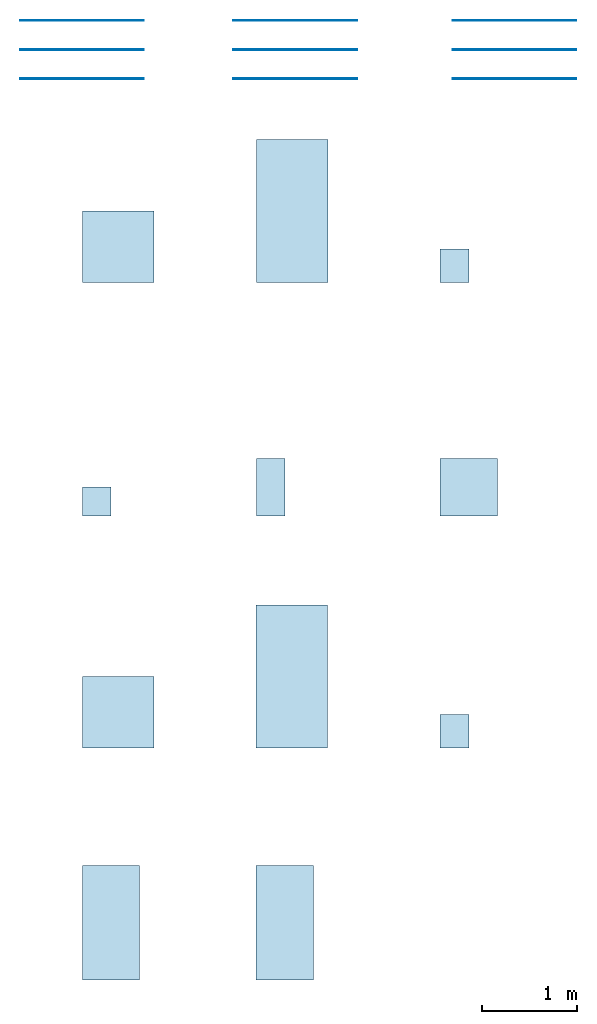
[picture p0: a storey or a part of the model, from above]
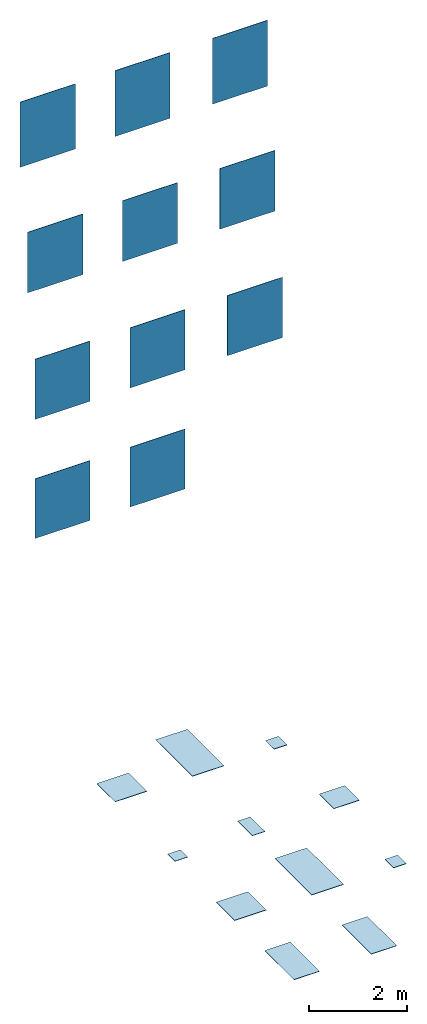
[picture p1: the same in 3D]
Properties of the parts of a building model (IFC2X3)

# File
Description: ViewDefinition [CoordinationView_V2.0], RevitIdentifiers [VersionGUID: 1a7853d5-8258-4d92-be9f-6eaaf23e1352, NumberOfSaves: 259], CoordinateReference [CoordinateBase: Shared Coordinates, ProjectSite: Internal]
File name: Project Number
Time: 2025-02-25T10:54:23+01:00
Written by: ODA SDAI 24.3
Made in: Autodesk Revit 24.1.11.26 (ENU) - IFC 24.1.11.26

# IfcProject, Project Number
LongName: Refin-Blended; Phase: Project Status

# IfcSite, Default
RefLatitude: 51, 30, 0, 549316; RefLongitude: 0, -7, -34, -450321; RefElevation: 0 mm

# IfcBuilding
Pset_BuildingCommon - NumberOfStoreys: 1

# IfcBuildingStorey: Level:Circle Head - Project Datum (2)
Pset_AirSideSystemInformation - sets with these values: 2
Name | LongName = Name | Elevation (mm)
Level 0 | Level 0 | 0
Level 1 | Level 1 | 4000

# IfcSlab: Floor:Floor_Tiles_Refin-Prestigio_Travertino-Beige-Lucido-75x150 OM86, Floor:Floor_Tiles_Refin-Prestigio_Travertino-Beige-Lucido-75x150 OM86:324498
In: Level 0
Type - PredefinedType: FLOOR; Material: Prestigio Travertino-Beige-Lucido-75x150 OM86 9 mm, <Unnamed> 1 mm
Type - Pset_ConcreteElementGeneral - FireRating: INERT
Type - Pset_ElementShading - Color: IVORY-BEIGE
Type - Pset_FireRatingProperties - SurfaceSpreadOfFlame: INERT
Type - Pset_ManufacturerOccurrence - BarCode: N/A; SerialNumber: N/A
Type - Pset_ManufacturerTypeInformation - ArticleNumber: OM86; ModelReference: OM86; ModelLabel: BEIGE LUCIDO 75X150; Manufacturer: info@refin.it; ProductionYear: N/A
Type - Pset_PrecastConcreteElementGeneral - SerialNumber: N/A
Type - Pset_ProductRequirements - Name: Prestigio_Travertino_Beige_Lucido_75X150; Category: Pr_35_93_96_19:Ceramic tiles
Type - Pset_QuantityTakeOff - Reference: N/A
Type - Pset_ReinforcementBarPitchOfSlab - Description: PORCELAIN STONEWARE TILE; Reference: N/A
Type - Pset_SlabCommon - Reference: N/A; IsExternal: no; AcousticRating: N/A; FireRating: INERT; SurfaceSpreadOfFlame: INERT
Type - Pset_Warranty - WarrantyContent: N/A; Exclusions: N/A
Pset_QuantityTakeOff - sets with these values: 2
Pset_SlabCommon - LoadBearing: no; PitchAngle: 0 deg

# IfcSlab: Floor:Floor_Tiles_Refin-Prestigio_Travertino-Beige-Lucido-75x75 OO01, Floor:Floor_Tiles_Refin-Prestigio_Travertino-Beige-Lucido-75x75 OO01:304668
In: Level 0
Type - PredefinedType: FLOOR; Material: Prestigio Travertino-Beige-Lucido-75x75 OO01 9 mm, <Unnamed> 1 mm
Type - Pset_ConcreteElementGeneral - FireRating: INERT
Type - Pset_ElementShading - Color: IVORY-BEIGE
Type - Pset_FireRatingProperties - SurfaceSpreadOfFlame: INERT
Type - Pset_ManufacturerOccurrence - BarCode: N/A; SerialNumber: N/A
Type - Pset_ManufacturerTypeInformation - ArticleNumber: OO01; ModelReference: OO01; ModelLabel: BEIGE LUCIDO 75X75; Manufacturer: info@refin.it; ProductionYear: N/A
Type - Pset_PrecastConcreteElementGeneral - SerialNumber: N/A
Type - Pset_ProductRequirements - Name: Prestigio_Travertino_Beige_Lucido_75X75; Category: Pr_35_93_96_19:Ceramic tiles
Type - Pset_QuantityTakeOff - Reference: N/A
Type - Pset_ReinforcementBarPitchOfSlab - Description: PORCELAIN STONEWARE TILE; Reference: N/A
Type - Pset_SlabCommon - Reference: N/A; IsExternal: no; AcousticRating: N/A; FireRating: INERT; SurfaceSpreadOfFlame: INERT
Type - Pset_Warranty - WarrantyContent: N/A; Exclusions: N/A
Pset_QuantityTakeOff - sets with these values: 2
Pset_SlabCommon - LoadBearing: no; PitchAngle: 0 deg

# IfcSlab: Floor:Floor_Tiles_Refin-Prestigio_Travertino-Beige-Lucido-Mosaico-Cube 30.4x35.2 OO30, Floor:Floor_Tiles_Refin-Prestigio_Travertino-Beige-Lucido-Mosaico-Cube 30.4x35.2 OO30:285295
In: Level 0
Type - PredefinedType: FLOOR; Material: Prestigio Travertino-Beige-Lucido-Mosaico-Cube 30.4x35.2 OO30 9 mm, <Unnamed> 1 mm
Type - Pset_ConcreteElementGeneral - FireRating: INERT
Type - Pset_ElementShading - Color: IVORY-BEIGE
Type - Pset_FireRatingProperties - SurfaceSpreadOfFlame: INERT
Type - Pset_ManufacturerOccurrence - BarCode: N/A; SerialNumber: N/A
Type - Pset_ManufacturerTypeInformation - ArticleNumber: OO30; ModelReference: OO30; ModelLabel: BEIGE LUCIDO MOSAICO CUBE 30.4X35.2; Manufacturer: info@refin.it; ProductionYear: N/A
Type - Pset_PrecastConcreteElementGeneral - SerialNumber: N/A
Type - Pset_ProductRequirements - Name: Prestigio_Travertino_Beige_Lucido_Mosaico_Cube_30.4X35.2; Category: Pr_35_93_96_19:Ceramic tiles
Type - Pset_QuantityTakeOff - Reference: N/A
Type - Pset_ReinforcementBarPitchOfSlab - Description: PORCELAIN STONEWARE TILE; Reference: N/A
Type - Pset_SlabCommon - Reference: N/A; IsExternal: no; AcousticRating: N/A; FireRating: INERT; SurfaceSpreadOfFlame: INERT
Type - Pset_Warranty - WarrantyContent: N/A; Exclusions: N/A
Pset_QuantityTakeOff - sets with these values: 2
Pset_SlabCommon - LoadBearing: no; PitchAngle: 0 deg

# IfcSlab: Floor:Floor_Tiles_Refin-Prestigio_Travertino-Beige-Lucido-Mosaico-T 30x30 OO36, Floor:Floor_Tiles_Refin-Prestigio_Travertino-Beige-Lucido-Mosaico-T 30x30 OO36:304956
In: Level 0
Type - PredefinedType: FLOOR; Material: Prestigio Travertino-Beige-Mix-Mosaico-T 30x30 OO36 9 mm, <Unnamed> 1 mm
Type - Pset_ConcreteElementGeneral - FireRating: INERT
Type - Pset_ElementShading - Color: IVORY-BEIGE
Type - Pset_FireRatingProperties - SurfaceSpreadOfFlame: INERT
Type - Pset_ManufacturerOccurrence - BarCode: N/A; SerialNumber: N/A
Type - Pset_ManufacturerTypeInformation - ArticleNumber: OO36; ModelReference: OO36; ModelLabel: BEIGE MIX MOSAICO T 3X30; Manufacturer: info@refin.it; ProductionYear: N/A
Type - Pset_PrecastConcreteElementGeneral - SerialNumber: N/A
Type - Pset_ProductRequirements - Name: Prestigio_Travertino_Beige_Mix_Mosaico_T_3X30; Category: Pr_35_93_96_19:Ceramic tiles
Type - Pset_QuantityTakeOff - Reference: N/A
Type - Pset_ReinforcementBarPitchOfSlab - Description: PORCELAIN STONEWARE TILE; Reference: N/A
Type - Pset_SlabCommon - Reference: N/A; IsExternal: no; AcousticRating: N/A; FireRating: INERT; SurfaceSpreadOfFlame: INERT
Type - Pset_Warranty - WarrantyContent: N/A; Exclusions: N/A
Pset_QuantityTakeOff - sets with these values: 2
Pset_SlabCommon - LoadBearing: no; PitchAngle: 0 deg

# IfcSlab: Floor:Floor_Tiles_Refin-Prestigio_Travertino-Beige-Soft-30x60 OO07, Floor:Floor_Tiles_Refin-Prestigio_Travertino-Beige-Soft-30x60 OO07:304948
In: Level 0
Type - PredefinedType: FLOOR; Material: Prestigio Travertino-Beige-Soft-30x60 OO07 9 mm, <Unnamed> 1 mm
Type - Pset_ConcreteElementGeneral - FireRating: INERT
Type - Pset_ElementShading - Color: IVORY-BEIGE
Type - Pset_FireRatingProperties - SurfaceSpreadOfFlame: INERT
Type - Pset_ManufacturerOccurrence - BarCode: N/A; SerialNumber: N/A
Type - Pset_ManufacturerTypeInformation - ArticleNumber: OO07; ModelReference: OO07; ModelLabel: BEIGE SOFT 30X60; Manufacturer: info@refin.it; ProductionYear: N/A
Type - Pset_PrecastConcreteElementGeneral - SerialNumber: N/A
Type - Pset_ProductRequirements - Name: Prestigio_Travertino_Beige_Soft_30X60; Category: Pr_35_93_96_19:Ceramic tiles
Type - Pset_QuantityTakeOff - Reference: N/A
Type - Pset_ReinforcementBarPitchOfSlab - Description: PORCELAIN STONEWARE TILE; Reference: N/A
Type - Pset_SlabCommon - Reference: N/A; IsExternal: no; AcousticRating: N/A; FireRating: INERT; SurfaceSpreadOfFlame: INERT
Type - Pset_Warranty - WarrantyContent: N/A; Exclusions: N/A
Pset_QuantityTakeOff - sets with these values: 2
Pset_SlabCommon - LoadBearing: no; PitchAngle: 0 deg

# IfcSlab: Floor:Floor_Tiles_Refin-Prestigio_Travertino-Beige-Soft-60x120 OZ35, Floor:Floor_Tiles_Refin-Prestigio_Travertino-Beige-Soft-60x120 OZ35:348506
In: Level 0
Type - PredefinedType: FLOOR; Material: Prestigio Travertino-Beige-Soft-60x120 OZ35 9 mm, <Unnamed> 1 mm
Type - Pset_ConcreteElementGeneral - FireRating: INERT
Type - Pset_ElementShading - Color: BEIGE
Type - Pset_FireRatingProperties - SurfaceSpreadOfFlame: INERT
Type - Pset_ManufacturerOccurrence - BarCode: N/A; SerialNumber: N/A
Type - Pset_ManufacturerTypeInformation - ArticleNumber: OZ35; ModelReference: OZ35; ModelLabel: BEIGE SOFT 60X120; Manufacturer: info@refin.it; ProductionYear: N/A
Type - Pset_PrecastConcreteElementGeneral - SerialNumber: N/A
Type - Pset_ProductRequirements - Name: Prestigio_Travertino_Beige_Soft_60X120; Category: Pr_35_93_96_19:Ceramic tiles
Type - Pset_QuantityTakeOff - Reference: N/A
Type - Pset_ReinforcementBarPitchOfSlab - Description: PORCELAIN STONEWARE TILE; Reference: N/A
Type - Pset_SlabCommon - Reference: N/A; IsExternal: no; AcousticRating: N/A; FireRating: INERT; SurfaceSpreadOfFlame: INERT
Type - Pset_Warranty - WarrantyContent: N/A; Exclusions: N/A
Pset_QuantityTakeOff - sets with these values: 2
Pset_SlabCommon - LoadBearing: no; PitchAngle: 0 deg

# IfcSlab: Floor:Floor_Tiles_Refin-Prestigio_Travertino-Beige-Soft-60x60 OO04, Floor:Floor_Tiles_Refin-Prestigio_Travertino-Beige-Soft-60x60 OO04:304932
In: Level 0
Type - PredefinedType: FLOOR; Material: Prestigio Travertino-Beige-Soft-60x60 OO04 9 mm, <Unnamed> 1 mm
Type - Pset_ConcreteElementGeneral - FireRating: INERT
Type - Pset_ElementShading - Color: IVORY-BEIGE
Type - Pset_FireRatingProperties - SurfaceSpreadOfFlame: INERT
Type - Pset_ManufacturerOccurrence - BarCode: N/A; SerialNumber: N/A
Type - Pset_ManufacturerTypeInformation - ArticleNumber: OO04; ModelReference: OO04; ModelLabel: BEIGE SOFT 60X60; Manufacturer: info@refin.it; ProductionYear: N/A
Type - Pset_PrecastConcreteElementGeneral - SerialNumber: N/A
Type - Pset_ProductRequirements - Name: Prestigio_Travertino_Beige_Soft_60X60; Category: Pr_35_93_96_19:Ceramic tiles
Type - Pset_QuantityTakeOff - Reference: N/A
Type - Pset_ReinforcementBarPitchOfSlab - Description: PORCELAIN STONEWARE TILE; Reference: N/A
Type - Pset_SlabCommon - Reference: N/A; IsExternal: no; AcousticRating: N/A; FireRating: INERT; SurfaceSpreadOfFlame: INERT
Type - Pset_Warranty - WarrantyContent: N/A; Exclusions: N/A
Pset_QuantityTakeOff - sets with these values: 2
Pset_SlabCommon - LoadBearing: no; PitchAngle: 0 deg

# IfcSlab: Floor:Floor_Tiles_Refin-Prestigio_Travertino-Beige-Soft-75x150 OM83, Floor:Floor_Tiles_Refin-Prestigio_Travertino-Beige-Soft-75x150 OM83:339635
In: Level 0
Type - PredefinedType: FLOOR; Material: Prestigio Travertino-Beige-Soft-75x150 OM83 9 mm, <Unnamed> 1 mm
Type - Pset_ConcreteElementGeneral - FireRating: INERT
Type - Pset_ElementShading - Color: IVORY-BEIGE
Type - Pset_FireRatingProperties - SurfaceSpreadOfFlame: INERT
Type - Pset_ManufacturerOccurrence - BarCode: N/A; SerialNumber: N/A
Type - Pset_ManufacturerTypeInformation - ArticleNumber: OM83; ModelReference: OM83; ModelLabel: BEIGE SOFT 75X150; Manufacturer: info@refin.it; ProductionYear: N/A
Type - Pset_PrecastConcreteElementGeneral - SerialNumber: N/A
Type - Pset_ProductRequirements - Name: Prestigio_Travertino_Beige_Soft_75X150; Category: Pr_35_93_96_19:Ceramic tiles
Type - Pset_QuantityTakeOff - Reference: N/A
Type - Pset_ReinforcementBarPitchOfSlab - Description: PORCELAIN STONEWARE TILE; Reference: N/A
Type - Pset_SlabCommon - Reference: N/A; IsExternal: no; AcousticRating: N/A; FireRating: INERT; SurfaceSpreadOfFlame: INERT
Type - Pset_Warranty - WarrantyContent: N/A; Exclusions: N/A
Pset_QuantityTakeOff - sets with these values: 2
Pset_SlabCommon - LoadBearing: no; PitchAngle: 0 deg

# IfcSlab: Floor:Floor_Tiles_Refin-Prestigio_Travertino-Beige-Soft-75x75 ON98, Floor:Floor_Tiles_Refin-Prestigio_Travertino-Beige-Soft-75x75 ON98:305509
In: Level 0
Type - PredefinedType: FLOOR; Material: Prestigio Travertino-Beige-Soft-75x75 ON98 9 mm, <Unnamed> 1 mm
Type - Pset_ConcreteElementGeneral - FireRating: INERT
Type - Pset_ElementShading - Color: IVORY-BEIGE
Type - Pset_FireRatingProperties - SurfaceSpreadOfFlame: INERT
Type - Pset_ManufacturerOccurrence - BarCode: N/A; SerialNumber: N/A
Type - Pset_ManufacturerTypeInformation - ArticleNumber: ON98; ModelReference: ON98; ModelLabel: BEIGE SOFT 75X75; Manufacturer: info@refin.it; ProductionYear: N/A
Type - Pset_PrecastConcreteElementGeneral - SerialNumber: N/A
Type - Pset_ProductRequirements - Name: Prestigio_Travertino_Beige_Soft_75X75; Category: Pr_35_93_96_19:Ceramic tiles
Type - Pset_QuantityTakeOff - Reference: N/A
Type - Pset_ReinforcementBarPitchOfSlab - Description: PORCELAIN STONEWARE TILE; Reference: N/A
Type - Pset_SlabCommon - Reference: N/A; IsExternal: no; AcousticRating: N/A; FireRating: INERT; SurfaceSpreadOfFlame: INERT
Type - Pset_Warranty - WarrantyContent: N/A; Exclusions: N/A
Pset_QuantityTakeOff - sets with these values: 2
Pset_SlabCommon - LoadBearing: no; PitchAngle: 0 deg

# IfcSlab: Floor:Floor_Tiles_Refin-Prestigio_Travertino-Beige-Soft-Mosaico-Cube 30.4x35.2 OO33, Floor:Floor_Tiles_Refin-Prestigio_Travertino-Beige-Soft-Mosaico-Cube 30.4x35.2 OO33:339650
In: Level 0
Type - PredefinedType: FLOOR; Material: Prestigio Travertino-Beige-Soft-Mosaico-Cube 30.4x35.2 OO33 9 mm, <Unnamed> 1 mm
Type - Pset_ConcreteElementGeneral - FireRating: INERT
Type - Pset_ElementShading - Color: IVORY-BEIGE
Type - Pset_FireRatingProperties - SurfaceSpreadOfFlame: INERT
Type - Pset_ManufacturerOccurrence - BarCode: N/A; SerialNumber: N/A
Type - Pset_ManufacturerTypeInformation - ArticleNumber: OO33; ModelReference: OO33; ModelLabel: BEIGE SOFT MOSAICO CUBE 30.4X35.2; Manufacturer: info@refin.it; ProductionYear: N/A
Type - Pset_PrecastConcreteElementGeneral - SerialNumber: N/A
Type - Pset_ProductRequirements - Name: Prestigio_Travertino_Beige_Soft_Mosaico_Cube_30.4X35.2; Category: Pr_35_93_96_19:Ceramic tiles
Type - Pset_QuantityTakeOff - Reference: N/A
Type - Pset_ReinforcementBarPitchOfSlab - Description: PORCELAIN STONEWARE TILE; Reference: N/A
Type - Pset_SlabCommon - Reference: N/A; IsExternal: no; AcousticRating: N/A; FireRating: INERT; SurfaceSpreadOfFlame: INERT
Type - Pset_Warranty - WarrantyContent: N/A; Exclusions: N/A
Pset_QuantityTakeOff - sets with these values: 2
Pset_SlabCommon - LoadBearing: no; PitchAngle: 0 deg

# IfcSlab: Floor:Floor_Tiles_Refin-Prestigio_Travertino-Dorico-Beige-Soft-60x120 RK78, Floor:Floor_Tiles_Refin-Prestigio_Travertino-Dorico-Beige-Soft-60x120 RK78:349143
In: Level 0
Type - PredefinedType: FLOOR; Material: Prestigio Travertino-Dorico-Beige-Soft-60x120 RK78 9 mm, <Unnamed> 1 mm
Type - Pset_ConcreteElementGeneral - FireRating: INERT
Type - Pset_ElementShading - Color: BEIGE
Type - Pset_FireRatingProperties - SurfaceSpreadOfFlame: INERT
Type - Pset_ManufacturerOccurrence - BarCode: N/A; SerialNumber: N/A
Type - Pset_ManufacturerTypeInformation - ArticleNumber: RK78; ModelReference: RK78; ModelLabel: DORICO BEIGE SOFT 60X120; Manufacturer: info@refin.it; ProductionYear: N/A
Type - Pset_PrecastConcreteElementGeneral - SerialNumber: N/A
Type - Pset_ProductRequirements - Name: Prestigio_Travertino_Dorico_Beige_Soft_60X120; Category: Pr_35_93_96_19:Ceramic tiles
Type - Pset_QuantityTakeOff - Reference: N/A
Type - Pset_ReinforcementBarPitchOfSlab - Description: PORCELAIN STONEWARE TILE; Reference: N/A
Type - Pset_SlabCommon - Reference: N/A; IsExternal: no; AcousticRating: N/A; FireRating: INERT; SurfaceSpreadOfFlame: INERT
Type - Pset_Warranty - WarrantyContent: N/A; Exclusions: N/A
Pset_QuantityTakeOff - sets with these values: 2
Pset_SlabCommon - LoadBearing: no; PitchAngle: 0 deg

# IfcWallStandardCase: Basic Wall:Floor_Tiles_Refin-Prestigio_Travertino-Beige-Lucido-75x150 OM86, Basic Wall:Floor_Tiles_Refin-Prestigio_Travertino-Beige-Lucido-75x150 OM86:333696
In: Level 0
Type - PredefinedType: STANDARD; Material: <Unnamed> 1 mm, Prestigio Travertino-Beige-Lucido-75x150 OM86 9 mm
Type - Pset_ElementShading - Color: IVORY-BEIGE
Type - Pset_FireRatingProperties - SurfaceSpreadOfFlame: INERT
Type - Pset_ManufacturerOccurrence - BarCode: N/A; SerialNumber: N/A
Type - Pset_ManufacturerTypeInformation - ArticleNumber: OM86; ModelReference: OM86; ModelLabel: BEIGE LUCIDO 75X150; Manufacturer: info@refin.it; ProductionYear: N/A
Type - Pset_PrecastConcreteElementGeneral - SerialNumber: N/A
Type - Pset_ProductRequirements - Name: Prestigio Travertino_Beige_Lucido_75X150; Category: Pr_35_93_96_19:Ceramic tiles
Type - Pset_QuantityTakeOff - Reference: N/A
Type - Pset_ReinforcementBarPitchOfWall - Description: PORCELAIN STONEWARE TILE; Reference: N/A
Type - Pset_WallCommon - Reference: N/A; IsExternal: no; AcousticRating: N/A; SurfaceSpreadOfFlame: INERT
Type - Pset_Warranty - WarrantyContent: N/A; Exclusions: N/A
Pset_QuantityTakeOff - sets with these values: 2
Pset_WallCommon - LoadBearing: no; ExtendToStructure: no

# IfcWallStandardCase: Basic Wall:Floor_Tiles_Refin-Prestigio_Travertino-Beige-Lucido-75x75 OO01, Basic Wall:Floor_Tiles_Refin-Prestigio_Travertino-Beige-Lucido-75x75 OO01:334895
In: Level 0
Type - PredefinedType: STANDARD; Material: <Unnamed> 1 mm, Prestigio Travertino-Beige-Lucido-75x75 OO01 9 mm
Type - Pset_ElementShading - Color: IVORY-BEIGE
Type - Pset_FireRatingProperties - SurfaceSpreadOfFlame: INERT
Type - Pset_ManufacturerOccurrence - BarCode: N/A; SerialNumber: N/A
Type - Pset_ManufacturerTypeInformation - ArticleNumber: OO01; ModelReference: OO01; ModelLabel: BEIGE LUCIDO 75X75; Manufacturer: info@refin.it; ProductionYear: N/A
Type - Pset_PrecastConcreteElementGeneral - SerialNumber: N/A
Type - Pset_ProductRequirements - Name: Prestigio Travertino_Beige_Lucido_75X75; Category: Pr_35_93_96_19:Ceramic tiles
Type - Pset_QuantityTakeOff - Reference: N/A
Type - Pset_ReinforcementBarPitchOfWall - Description: PORCELAIN STONEWARE TILE; Reference: N/A
Type - Pset_WallCommon - Reference: N/A; IsExternal: no; AcousticRating: N/A; SurfaceSpreadOfFlame: INERT
Type - Pset_Warranty - WarrantyContent: N/A; Exclusions: N/A
Pset_QuantityTakeOff - sets with these values: 2
Pset_WallCommon - LoadBearing: no; ExtendToStructure: no

# IfcWallStandardCase: Basic Wall:Floor_Tiles_Refin-Prestigio_Travertino-Beige-Lucido-Mosaico-Cube 30.4x35.2 OO30, Basic Wall:Floor_Tiles_Refin-Prestigio_Travertino-Beige-Lucido-Mosaico-Cube 30.4x35.2 OO30:334553
In: Level 0
Type - PredefinedType: STANDARD; Material: <Unnamed> 1 mm, Prestigio Travertino-Beige-Lucido-Mosaico-Cube 30.4x35.2 OO30 9 mm
Type - Pset_ElementShading - Color: IVORY-BEIGE
Type - Pset_FireRatingProperties - SurfaceSpreadOfFlame: INERT
Type - Pset_ManufacturerOccurrence - BarCode: N/A; SerialNumber: N/A
Type - Pset_ManufacturerTypeInformation - ArticleNumber: OO30; ModelReference: OO30; ModelLabel: BEIGE LUCIDO MOSAICO CUBE 30.4X35.2; Manufacturer: info@refin.it; ProductionYear: N/A
Type - Pset_PrecastConcreteElementGeneral - SerialNumber: N/A
Type - Pset_ProductRequirements - Name: Prestigio Travertino_Beige_Lucido_Mosaico_Cube_30.4X35.2; Category: Pr_35_93_96_19:Ceramic tiles
Type - Pset_QuantityTakeOff - Reference: N/A
Type - Pset_ReinforcementBarPitchOfWall - Description: PORCELAIN STONEWARE TILE; Reference: N/A
Type - Pset_WallCommon - Reference: N/A; IsExternal: no; AcousticRating: N/A; SurfaceSpreadOfFlame: INERT
Type - Pset_Warranty - WarrantyContent: N/A; Exclusions: N/A
Pset_QuantityTakeOff - sets with these values: 2
Pset_WallCommon - LoadBearing: no; ExtendToStructure: no

# IfcWallStandardCase: Basic Wall:Floor_Tiles_Refin-Prestigio_Travertino-Beige-Lucido-Mosaico-T 30x30 OO36, Basic Wall:Floor_Tiles_Refin-Prestigio_Travertino-Beige-Lucido-Mosaico-T 30x30 OO36:335038
In: Level 0
Type - PredefinedType: STANDARD; Material: <Unnamed> 1 mm, Prestigio Travertino-Beige-Mix-Mosaico-T 30x30 OO36 9 mm
Type - Pset_ElementShading - Color: IVORY-BEIGE
Type - Pset_FireRatingProperties - SurfaceSpreadOfFlame: INERT
Type - Pset_ManufacturerOccurrence - BarCode: N/A; SerialNumber: N/A
Type - Pset_ManufacturerTypeInformation - ArticleNumber: OO36; ModelReference: OO36; ModelLabel: BEIGE MIX MOSAICO T 30X30; Manufacturer: info@refin.it; ProductionYear: N/A
Type - Pset_PrecastConcreteElementGeneral - SerialNumber: N/A
Type - Pset_ProductRequirements - Name: Prestigio Travertino_BeigeMix_Mosaico_T_30X30; Category: Pr_35_93_96_19:Ceramic tiles
Type - Pset_QuantityTakeOff - Reference: N/A
Type - Pset_ReinforcementBarPitchOfWall - Description: PORCELAIN STONEWARE TILE; Reference: N/A
Type - Pset_WallCommon - Reference: N/A; IsExternal: no; AcousticRating: N/A; SurfaceSpreadOfFlame: INERT
Type - Pset_Warranty - WarrantyContent: N/A; Exclusions: N/A
Pset_QuantityTakeOff - sets with these values: 2
Pset_WallCommon - LoadBearing: no; ExtendToStructure: no

# IfcWallStandardCase: Basic Wall:Floor_Tiles_Refin-Prestigio_Travertino-Beige-Soft-30x60 OO07, Basic Wall:Floor_Tiles_Refin-Prestigio_Travertino-Beige-Soft-30x60 OO07:335490
In: Level 0
Type - PredefinedType: STANDARD; Material: <Unnamed> 1 mm, Prestigio Travertino-Beige-Soft-30x60 OO07 9 mm
Type - Pset_ElementShading - Color: IVORY-BEIGE
Type - Pset_FireRatingProperties - SurfaceSpreadOfFlame: INERT
Type - Pset_ManufacturerOccurrence - BarCode: N/A; SerialNumber: N/A
Type - Pset_ManufacturerTypeInformation - ArticleNumber: OO07; ModelReference: OO07; ModelLabel: BEIGE SOFT 30X60; Manufacturer: info@refin.it; ProductionYear: N/A
Type - Pset_PrecastConcreteElementGeneral - SerialNumber: N/A
Type - Pset_ProductRequirements - Name: Prestigio Travertino_Beige_Soft_30X60; Category: Pr_35_93_96_19:Ceramic tiles
Type - Pset_QuantityTakeOff - Reference: N/A
Type - Pset_ReinforcementBarPitchOfWall - Description: PORCELAIN STONEWARE TILE; Reference: N/A
Type - Pset_WallCommon - Reference: N/A; IsExternal: no; AcousticRating: N/A; SurfaceSpreadOfFlame: INERT
Type - Pset_Warranty - WarrantyContent: N/A; Exclusions: N/A
Pset_QuantityTakeOff - sets with these values: 2
Pset_WallCommon - LoadBearing: no; ExtendToStructure: no

# IfcWallStandardCase: Basic Wall:Floor_Tiles_Refin-Prestigio_Travertino-Beige-Soft-60x120 OZ35, Basic Wall:Floor_Tiles_Refin-Prestigio_Travertino-Beige-Soft-60x120 OZ35:348591
In: Level 0
Type - PredefinedType: STANDARD; Material: <Unnamed> 1 mm, Prestigio Travertino-Beige-Soft-60x120 OZ35 9 mm
Type - Pset_ElementShading - Color: BEIGE
Type - Pset_FireRatingProperties - SurfaceSpreadOfFlame: INERT
Type - Pset_ManufacturerOccurrence - BarCode: N/A; SerialNumber: N/A
Type - Pset_ManufacturerTypeInformation - ArticleNumber: OZ35; ModelReference: OZ35; ModelLabel: BEIGE SOFT 60X120; Manufacturer: info@refin.it; ProductionYear: N/A
Type - Pset_PrecastConcreteElementGeneral - SerialNumber: N/A
Type - Pset_ProductRequirements - Name: Prestigio Travertino_Beige_Soft_60X120; Category: Pr_35_93_96_19:Ceramic tiles
Type - Pset_QuantityTakeOff - Reference: N/A
Type - Pset_ReinforcementBarPitchOfWall - Description: PORCELAIN STONEWARE TILE; Reference: N/A
Type - Pset_WallCommon - Reference: N/A; IsExternal: no; AcousticRating: N/A; SurfaceSpreadOfFlame: INERT
Type - Pset_Warranty - WarrantyContent: N/A; Exclusions: N/A
Pset_QuantityTakeOff - sets with these values: 2
Pset_WallCommon - LoadBearing: no; ExtendToStructure: no

# IfcWallStandardCase: Basic Wall:Floor_Tiles_Refin-Prestigio_Travertino-Beige-Soft-60x60 OO04, Basic Wall:Floor_Tiles_Refin-Prestigio_Travertino-Beige-Soft-60x60 OO04:335882
In: Level 0
Type - PredefinedType: STANDARD; Material: <Unnamed> 1 mm, Prestigio Travertino-Beige-Soft-60x60 OO04 9 mm
Type - Pset_ElementShading - Color: IVORY-BEIGE
Type - Pset_FireRatingProperties - SurfaceSpreadOfFlame: INERT
Type - Pset_ManufacturerOccurrence - BarCode: N/A; SerialNumber: N/A
Type - Pset_ManufacturerTypeInformation - ArticleNumber: OO04; ModelReference: OO04; ModelLabel: BEIGE SOFT 60X60; Manufacturer: info@refin.it; ProductionYear: N/A
Type - Pset_PrecastConcreteElementGeneral - SerialNumber: N/A
Type - Pset_ProductRequirements - Name: Prestigio Travertino_Beige_Soft_60X60; Category: Pr_35_93_96_19:Ceramic tiles
Type - Pset_QuantityTakeOff - Reference: N/A
Type - Pset_ReinforcementBarPitchOfWall - Description: PORCELAIN STONEWARE TILE; Reference: N/A
Type - Pset_WallCommon - Reference: N/A; IsExternal: no; AcousticRating: N/A; SurfaceSpreadOfFlame: INERT
Type - Pset_Warranty - WarrantyContent: N/A; Exclusions: N/A
Pset_QuantityTakeOff - sets with these values: 2
Pset_WallCommon - LoadBearing: no; ExtendToStructure: no

# IfcWallStandardCase: Basic Wall:Floor_Tiles_Refin-Prestigio_Travertino-Beige-Soft-75x150 OM83, Basic Wall:Floor_Tiles_Refin-Prestigio_Travertino-Beige-Soft-75x150 OM83:339715
In: Level 0
Type - PredefinedType: STANDARD; Material: <Unnamed> 1 mm, Prestigio Travertino-Beige-Soft-75x150 OM83 9 mm
Type - Pset_ElementShading - Color: IVORY-BEIGE
Type - Pset_FireRatingProperties - SurfaceSpreadOfFlame: INERT
Type - Pset_ManufacturerOccurrence - BarCode: N/A; SerialNumber: N/A
Type - Pset_ManufacturerTypeInformation - ArticleNumber: OM83; ModelReference: OM83; ModelLabel: BEIGE SOFT 75X150; Manufacturer: info@refin.it; ProductionYear: N/A
Type - Pset_PrecastConcreteElementGeneral - SerialNumber: N/A
Type - Pset_ProductRequirements - Name: Prestigio Travertino_Beige_Soft_75X150; Category: Pr_35_93_96_19:Ceramic tiles
Type - Pset_QuantityTakeOff - Reference: N/A
Type - Pset_ReinforcementBarPitchOfWall - Description: PORCELAIN STONEWARE TILE; Reference: N/A
Type - Pset_WallCommon - Reference: N/A; IsExternal: no; AcousticRating: N/A; SurfaceSpreadOfFlame: INERT
Type - Pset_Warranty - WarrantyContent: N/A; Exclusions: N/A
Pset_QuantityTakeOff - sets with these values: 2
Pset_WallCommon - LoadBearing: no; ExtendToStructure: no

# IfcWallStandardCase: Basic Wall:Floor_Tiles_Refin-Prestigio_Travertino-Beige-Soft-75x75 ON98, Basic Wall:Floor_Tiles_Refin-Prestigio_Travertino-Beige-Soft-75x75 ON98:336183
In: Level 0
Type - PredefinedType: STANDARD; Material: <Unnamed> 1 mm, Prestigio Travertino-Beige-Soft-75x75 ON98 9 mm
Type - Pset_ElementShading - Color: IVORY-BEIGE
Type - Pset_FireRatingProperties - SurfaceSpreadOfFlame: INERT
Type - Pset_ManufacturerOccurrence - BarCode: N/A; SerialNumber: N/A
Type - Pset_ManufacturerTypeInformation - ArticleNumber: ON98; ModelReference: ON98; ModelLabel: BEIGE SOFT 75X75; Manufacturer: info@refin.it; ProductionYear: N/A
Type - Pset_PrecastConcreteElementGeneral - SerialNumber: N/A
Type - Pset_ProductRequirements - Name: Prestigio Travertino_Beige_Soft_75X75; Category: Pr_35_93_96_19:Ceramic tiles
Type - Pset_QuantityTakeOff - Reference: N/A
Type - Pset_ReinforcementBarPitchOfWall - Description: PORCELAIN STONEWARE TILE; Reference: N/A
Type - Pset_WallCommon - Reference: N/A; IsExternal: no; AcousticRating: N/A; SurfaceSpreadOfFlame: INERT
Type - Pset_Warranty - WarrantyContent: N/A; Exclusions: N/A
Pset_QuantityTakeOff - sets with these values: 2
Pset_WallCommon - LoadBearing: no; ExtendToStructure: no

# IfcWallStandardCase: Basic Wall:Floor_Tiles_Refin-Prestigio_Travertino-Beige-Soft-Mosaico-Cube 30.4x35.2 OO33, Basic Wall:Floor_Tiles_Refin-Prestigio_Travertino-Beige-Soft-Mosaico-Cube 30.4x35.2 OO33:339723
In: Level 0
Type - PredefinedType: STANDARD; Material: <Unnamed> 1 mm, Prestigio Travertino-Beige-Soft-Mosaico-Cube 30.4x35.2 OO33 9 mm
Type - Pset_ElementShading - Color: IVORY-BEIGE
Type - Pset_FireRatingProperties - SurfaceSpreadOfFlame: INERT
Type - Pset_ManufacturerOccurrence - BarCode: N/A; SerialNumber: N/A
Type - Pset_ManufacturerTypeInformation - ArticleNumber: OO33; ModelReference: OO33; ModelLabel: BEIGE SOFT MOSAICO CUBE 30.4X35.2; Manufacturer: info@refin.it; ProductionYear: N/A
Type - Pset_PrecastConcreteElementGeneral - SerialNumber: N/A
Type - Pset_ProductRequirements - Name: Prestigio Travertino_Beige_Soft_Mosaico_Cube_30.4X35.2; Category: Pr_35_93_96_19:Ceramic tiles
Type - Pset_QuantityTakeOff - Reference: N/A
Type - Pset_ReinforcementBarPitchOfWall - Description: PORCELAIN STONEWARE TILE; Reference: N/A
Type - Pset_WallCommon - Reference: N/A; IsExternal: no; AcousticRating: N/A; SurfaceSpreadOfFlame: INERT
Type - Pset_Warranty - WarrantyContent: N/A; Exclusions: N/A
Pset_QuantityTakeOff - sets with these values: 2
Pset_WallCommon - LoadBearing: no; ExtendToStructure: no

# IfcWallStandardCase: Basic Wall:Floor_Tiles_Refin-Prestigio_Travertino-Dorico-Beige-Soft-60x120 RK78, Basic Wall:Floor_Tiles_Refin-Prestigio_Travertino-Dorico-Beige-Soft-60x120 RK78:349261
In: Level 0
Type - PredefinedType: STANDARD; Material: <Unnamed> 1 mm, Prestigio Travertino-Dorico-Beige-Soft-60x120 RK78 9 mm
Type - Pset_ElementShading - Color: BEIGE
Type - Pset_FireRatingProperties - SurfaceSpreadOfFlame: INERT
Type - Pset_ManufacturerOccurrence - BarCode: N/A; SerialNumber: N/A
Type - Pset_ManufacturerTypeInformation - ArticleNumber: RK78; ModelReference: RK78; ModelLabel: DORICO BEIGE SOFT 60X120; Manufacturer: info@refin.it; ProductionYear: N/A
Type - Pset_PrecastConcreteElementGeneral - SerialNumber: N/A
Type - Pset_ProductRequirements - Name: Prestigio Travertino_Dorico_Beige_Soft_60X120; Category: Pr_35_93_96_19:Ceramic tiles
Type - Pset_QuantityTakeOff - Reference: N/A
Type - Pset_ReinforcementBarPitchOfWall - Description: PORCELAIN STONEWARE TILE; Reference: N/A
Type - Pset_WallCommon - Reference: N/A; IsExternal: no; AcousticRating: N/A; SurfaceSpreadOfFlame: INERT
Type - Pset_Warranty - WarrantyContent: N/A; Exclusions: N/A
Pset_QuantityTakeOff - sets with these values: 2
Pset_WallCommon - LoadBearing: no; ExtendToStructure: no
